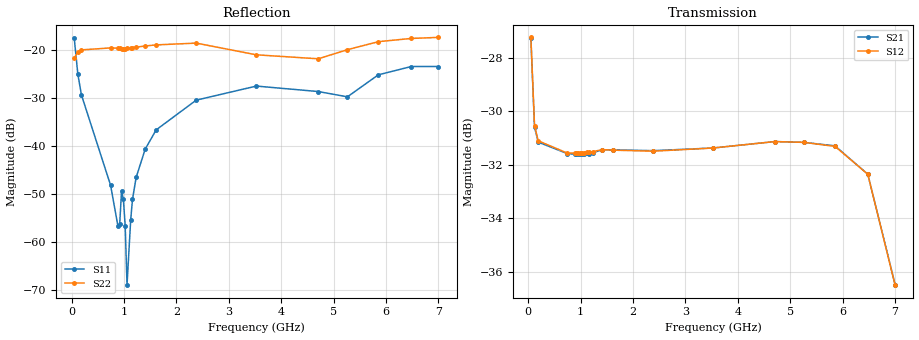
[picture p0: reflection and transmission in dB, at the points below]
! Integrated Device Technology
! Corporate Headquarters
! 6024 Silver Creek Valley Road
! San Jose, CA 95138  USA
! Phone:  1-408-284-8200
! Toll Free:  1-800-223-1366
! Webpage:  http://www.idt.com/
! Timing and RF Division
! 515 Groton Road, Suite 102
! Westford, MA 01886-6024
! Device:  F2258
! Description: Voltage Variable RF Attenuator
! Frequency:  50.0 -  6000.00 MHz
! Package:  3x3 mm Thin QFN Plastic Package: 16 pin
! Ports:  2 RF, 2 DC
!  Pin  1  = NC
!  Pin  2  = NC
!  Pin  3  = RF2  = Port 2
!  Pin  4  = GND
!  Pin  5  = Vdd
!  Pin  6  = NC
!  Pin  7  = VCTRL
!  Pin  8  = NC
!  Pin  9  = GND
!  Pin 10  = RF1  = Port 1
!  Pin 11  = NC
!  Pin 12  = NC
!  Pin 13  = NC
!  Pin 14  = NC
!  Pin 15  = NC
!  Pin 16  = NC
! Vcntrl:  1.720 Volts
! Vdd:  +3.300 Volts
! Current:  1.157 mA
! Data:  The device was measured on a the F2258 evaluation board which has
!  individual transmission lines to the RF pins.  Data was collected
!  using a calibrated network analyzer.  The evaluation board was
!  de-embedded using a TRL calibration technique.
!  The reference plane is the edge of the package pin.
! Misc:  SN 10
!  Action Tracker AT0285
! Date Measured:  2014-12-10
! Date:  2016-01-13  MJV
! Note:
!  Integrated Device Technology supplies this data as a sample of measured
!  data at the package pin for this product.  Your particular data for this
!  product may vary.
!  Data was taken at 25 degrees C.
!  Integrated Device Technology reserves the right to change this data at anytime.
!Freq_(GHz)  S11M_(dB)  S11P_(deg)  S21M_(dB)  S21P_(deg)  S12M_(dB)  S12P_(deg)  S22M_(dB)  S22P_(deg)
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# GHz S dB R 50
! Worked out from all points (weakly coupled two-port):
!   201 points, 50 MHz to 7 GHz, reference 50 ohm
!   highest |S21| = -27.27 dB at 50 MHz (marker M1); lowest = -36.5 dB at 7 GHz (marker M2)
!   lowest |S11| = -68.9 dB at 1.058 GHz (marker M3), VSWR 1.00, Z = 50 + j0.0236 ohm
!   |S11| at or under -10 dB: start of sweep to end of sweep
!   |S22| runs from -22.8 to -17.4 dB; largest |S21 - S12| = 0.00026
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0.05  -17.52 -110.3  -27.27 -54.3  -27.24 -54.2  -21.74 -60.0
0.1195  -25.10 -105.7  -30.58 -28.7  -30.53 -28.7  -20.46 -17.8
0.189  -29.43 -107.6  -31.15 -19.7  -31.10 -19.7  -20.04 -11.2
0.745  -48.20 -132.2  -31.58 -10.2  -31.56 -10.3  -19.63 -8.4
0.884  -56.64 168.1  -31.60 -10.4  -31.56 -10.4  -19.68 -10.0
0.91875  -56.15 142.2  -31.61 -10.5  -31.54 -10.5  -19.65 -10.4
0.9535  -49.32 -153.1  -31.60 -10.5  -31.55 -10.6  -19.90 -9.6
0.98825  -51.11 -165.7  -31.59 -10.6  -31.55 -10.6  -19.88 -10.3
1.023  -56.62 -178.1  -31.59 -10.7  -31.56 -10.7  -19.81 -10.7
1.05775  -68.92 138.8  -31.58 -10.8  -31.55 -10.8  -19.74 -10.8
1.12725  -55.47 60.5  -31.56 -11.0  -31.53 -11.1  -19.64 -11.5
1.162  -51.11 49.9  -31.58 -11.2  -31.52 -11.2  -19.57 -11.8
1.2315  -46.55 35.6  -31.55 -11.6  -31.51 -11.6  -19.47 -12.3
1.40525  -40.64 28.7  -31.44 -12.8  -31.43 -12.8  -19.23 -13.4
1.61375  -36.66 29.6  -31.44 -14.3  -31.45 -14.3  -19.00 -15.5
2.37825  -30.48 46.3  -31.47 -19.8  -31.49 -19.8  -18.63 -20.6
3.525  -27.56 90.8  -31.37 -28.9  -31.37 -28.9  -21.06 -32.5
4.7065  -28.69 95.1  -31.13 -39.8  -31.13 -39.8  -21.89 -56.6
5.2625  -29.79 53.0  -31.16 -46.0  -31.16 -46.0  -20.00 -59.0
5.85325  -25.22 28.9  -31.29 -55.1  -31.31 -55.1  -18.33 -58.2
6.47875  -23.50 40.8  -32.35 -68.7  -32.35 -68.7  -17.66 -75.4
7  -23.49 84.0  -36.47 -69.4  -36.49 -69.3  -17.44 -124.3
